VERSION 5.7 ;
  NOWIREEXTENSIONATPIN ON ;
  DIVIDERCHAR "/" ;
  BUSBITCHARS "[]" ;
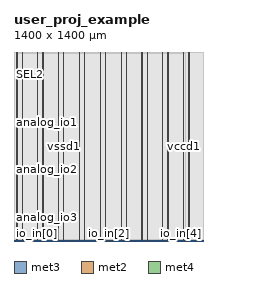
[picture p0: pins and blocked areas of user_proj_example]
MACRO user_proj_example
  CLASS BLOCK ;
  FOREIGN user_proj_example ;
  ORIGIN 0.000 0.000 ;
  SIZE 1400.000 BY 1400.000 ;
  PIN SEL2
    DIRECTION INPUT ;
    USE SIGNAL ;
    PORT
      LAYER met3 ;
        RECT 0.000 1224.040 4.000 1224.640 ;
    END
  END SEL2
  PIN analog_io1
    DIRECTION INPUT ;
    USE SIGNAL ;
    PORT
      LAYER met3 ;
        RECT 0.000 874.520 4.000 875.120 ;
    END
  END analog_io1
  PIN analog_io2
    DIRECTION INOUT ;
    USE SIGNAL ;
    PORT
      LAYER met3 ;
        RECT 0.000 525.000 4.000 525.600 ;
    END
  END analog_io2
  PIN analog_io3
    DIRECTION INPUT ;
    USE SIGNAL ;
    PORT
      LAYER met3 ;
        RECT 0.000 175.480 4.000 176.080 ;
    END
  END analog_io3
  PIN io_in[0]
    DIRECTION INPUT ;
    USE SIGNAL ;
    PORT
      LAYER met2 ;
        RECT 140.390 0.000 140.670 4.000 ;
    END
  END io_in[0]
  PIN io_in[1]
    DIRECTION INPUT ;
    USE SIGNAL ;
    PORT
      LAYER met2 ;
        RECT 420.070 0.000 420.350 4.000 ;
    END
  END io_in[1]
  PIN io_in[2]
    DIRECTION INPUT ;
    USE SIGNAL ;
    PORT
      LAYER met2 ;
        RECT 699.750 0.000 700.030 4.000 ;
    END
  END io_in[2]
  PIN io_in[3]
    DIRECTION INPUT ;
    USE SIGNAL ;
    PORT
      LAYER met2 ;
        RECT 979.430 0.000 979.710 4.000 ;
    END
  END io_in[3]
  PIN io_in[4]
    DIRECTION INPUT ;
    USE SIGNAL ;
    PORT
      LAYER met2 ;
        RECT 1259.110 0.000 1259.390 4.000 ;
    END
  END io_in[4]
  PIN vccd1
    DIRECTION INOUT ;
    USE POWER ;
    PORT
      LAYER met4 ;
        RECT 21.040 10.640 22.640 1387.440 ;
    END
    PORT
      LAYER met4 ;
        RECT 174.640 10.640 176.240 1387.440 ;
    END
    PORT
      LAYER met4 ;
        RECT 328.240 10.640 329.840 1387.440 ;
    END
    PORT
      LAYER met4 ;
        RECT 481.840 10.640 483.440 1387.440 ;
    END
    PORT
      LAYER met4 ;
        RECT 635.440 10.640 637.040 1387.440 ;
    END
    PORT
      LAYER met4 ;
        RECT 789.040 10.640 790.640 1387.440 ;
    END
    PORT
      LAYER met4 ;
        RECT 942.640 10.640 944.240 1387.440 ;
    END
    PORT
      LAYER met4 ;
        RECT 1096.240 10.640 1097.840 1387.440 ;
    END
    PORT
      LAYER met4 ;
        RECT 1249.840 10.640 1251.440 1387.440 ;
    END
  END vccd1
  PIN vssd1
    DIRECTION INOUT ;
    USE GROUND ;
    PORT
      LAYER met4 ;
        RECT 59.440 10.640 61.040 1387.440 ;
    END
    PORT
      LAYER met4 ;
        RECT 213.040 10.640 214.640 1387.440 ;
    END
    PORT
      LAYER met4 ;
        RECT 366.640 10.640 368.240 1387.440 ;
    END
    PORT
      LAYER met4 ;
        RECT 520.240 10.640 521.840 1387.440 ;
    END
    PORT
      LAYER met4 ;
        RECT 673.840 10.640 675.440 1387.440 ;
    END
    PORT
      LAYER met4 ;
        RECT 827.440 10.640 829.040 1387.440 ;
    END
    PORT
      LAYER met4 ;
        RECT 981.040 10.640 982.640 1387.440 ;
    END
    PORT
      LAYER met4 ;
        RECT 1134.640 10.640 1136.240 1387.440 ;
    END
    PORT
      LAYER met4 ;
        RECT 1288.240 10.640 1289.840 1387.440 ;
    END
    PORT
      LAYER met4 ;
        RECT 26.340 16.080 27.940 723.760 ;
    END
  END vssd1
  OBS
      LAYER li1 ;
        RECT 5.520 10.795 1394.260 1387.285 ;
      LAYER met1 ;
        RECT 5.520 10.640 1394.260 1387.440 ;
      LAYER met2 ;
        RECT 21.070 13.415 1251.410 1384.665 ;
      LAYER met3 ;
        RECT 21.050 13.435 1262.930 1384.645 ;
  END
END user_proj_example
END LIBRARY

